VERSION 5.7 ;
  NOWIREEXTENSIONATPIN ON ;
  DIVIDERCHAR "/" ;
  BUSBITCHARS "[]" ;
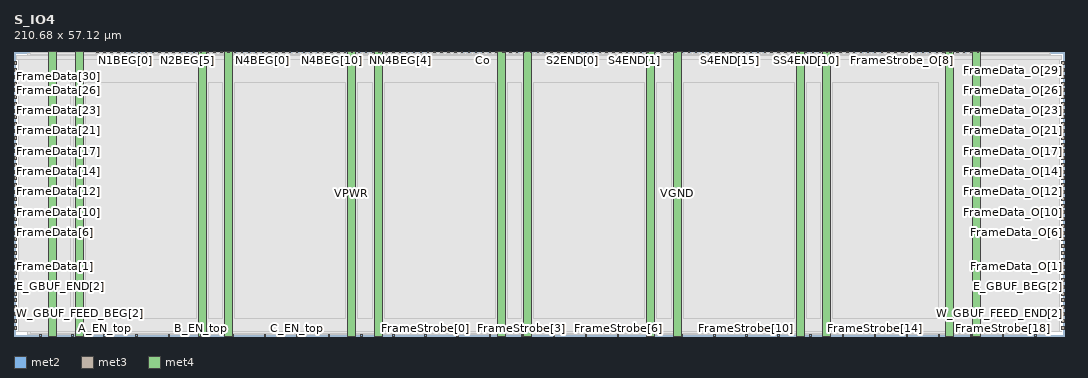
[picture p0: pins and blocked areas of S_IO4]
MACRO S_IO4
  CLASS BLOCK ;
  FOREIGN S_IO4 ;
  ORIGIN 0.000 0.000 ;
  SIZE 210.680 BY 57.120 ;
  PIN A_EN_top
    DIRECTION OUTPUT ;
    USE SIGNAL ;
    ANTENNADIFFAREA 0.702900 ;
    PORT
      LAYER met2 ;
        RECT 18.030 0.000 18.310 0.280 ;
    END
  END A_EN_top
  PIN A_IN_top
    DIRECTION OUTPUT ;
    USE SIGNAL ;
    ANTENNADIFFAREA 0.702900 ;
    PORT
      LAYER met2 ;
        RECT 11.590 0.000 11.870 0.280 ;
    END
  END A_IN_top
  PIN A_OUT_top
    DIRECTION INPUT ;
    USE SIGNAL ;
    ANTENNAGATEAREA 0.252000 ;
    PORT
      LAYER met2 ;
        RECT 5.150 0.000 5.430 0.280 ;
    END
  END A_OUT_top
  PIN B_EN_top
    DIRECTION OUTPUT ;
    USE SIGNAL ;
    ANTENNADIFFAREA 0.702900 ;
    PORT
      LAYER met2 ;
        RECT 37.350 0.000 37.630 0.280 ;
    END
  END B_EN_top
  PIN B_IN_top
    DIRECTION OUTPUT ;
    USE SIGNAL ;
    ANTENNADIFFAREA 0.702900 ;
    PORT
      LAYER met2 ;
        RECT 30.910 0.000 31.190 0.280 ;
    END
  END B_IN_top
  PIN B_OUT_top
    DIRECTION INPUT ;
    USE SIGNAL ;
    ANTENNAGATEAREA 0.252000 ;
    PORT
      LAYER met2 ;
        RECT 24.470 0.000 24.750 0.280 ;
    END
  END B_OUT_top
  PIN C_EN_top
    DIRECTION OUTPUT ;
    USE SIGNAL ;
    ANTENNADIFFAREA 0.702900 ;
    PORT
      LAYER met2 ;
        RECT 56.670 0.000 56.950 0.280 ;
    END
  END C_EN_top
  PIN C_IN_top
    DIRECTION OUTPUT ;
    USE SIGNAL ;
    ANTENNADIFFAREA 0.702900 ;
    PORT
      LAYER met2 ;
        RECT 50.230 0.000 50.510 0.280 ;
    END
  END C_IN_top
  PIN C_OUT_top
    DIRECTION INPUT ;
    USE SIGNAL ;
    ANTENNAGATEAREA 0.252000 ;
    PORT
      LAYER met2 ;
        RECT 43.790 0.000 44.070 0.280 ;
    END
  END C_OUT_top
  PIN Co
    DIRECTION OUTPUT ;
    USE SIGNAL ;
    PORT
      LAYER met2 ;
        RECT 93.930 56.840 94.210 57.120 ;
    END
  END Co
  PIN D_EN_top
    DIRECTION OUTPUT ;
    USE SIGNAL ;
    ANTENNADIFFAREA 0.702900 ;
    PORT
      LAYER met2 ;
        RECT 75.990 0.000 76.270 0.280 ;
    END
  END D_EN_top
  PIN D_IN_top
    DIRECTION OUTPUT ;
    USE SIGNAL ;
    ANTENNADIFFAREA 0.702900 ;
    PORT
      LAYER met2 ;
        RECT 69.550 0.000 69.830 0.280 ;
    END
  END D_IN_top
  PIN D_OUT_top
    DIRECTION INPUT ;
    USE SIGNAL ;
    ANTENNAGATEAREA 0.252000 ;
    PORT
      LAYER met2 ;
        RECT 63.110 0.000 63.390 0.280 ;
    END
  END D_OUT_top
  PIN E_GBUF_BEG[0]
    DIRECTION OUTPUT ;
    USE SIGNAL ;
    ANTENNADIFFAREA 0.702900 ;
    PORT
      LAYER met3 ;
        RECT 210.080 6.840 210.680 7.440 ;
    END
  END E_GBUF_BEG[0]
  PIN E_GBUF_BEG[1]
    DIRECTION OUTPUT ;
    USE SIGNAL ;
    ANTENNADIFFAREA 0.702900 ;
    PORT
      LAYER met3 ;
        RECT 210.080 8.200 210.680 8.800 ;
    END
  END E_GBUF_BEG[1]
  PIN E_GBUF_BEG[2]
    DIRECTION OUTPUT ;
    USE SIGNAL ;
    ANTENNADIFFAREA 0.702900 ;
    PORT
      LAYER met3 ;
        RECT 210.080 9.560 210.680 10.160 ;
    END
  END E_GBUF_BEG[2]
  PIN E_GBUF_BEG[3]
    DIRECTION OUTPUT ;
    USE SIGNAL ;
    ANTENNADIFFAREA 0.702900 ;
    PORT
      LAYER met3 ;
        RECT 210.080 10.920 210.680 11.520 ;
    END
  END E_GBUF_BEG[3]
  PIN E_GBUF_END[0]
    DIRECTION INPUT ;
    USE SIGNAL ;
    ANTENNAGATEAREA 0.954000 ;
    PORT
      LAYER met3 ;
        RECT 0.000 6.840 0.600 7.440 ;
    END
  END E_GBUF_END[0]
  PIN E_GBUF_END[1]
    DIRECTION INPUT ;
    USE SIGNAL ;
    ANTENNAGATEAREA 0.954000 ;
    PORT
      LAYER met3 ;
        RECT 0.000 8.200 0.600 8.800 ;
    END
  END E_GBUF_END[1]
  PIN E_GBUF_END[2]
    DIRECTION INPUT ;
    USE SIGNAL ;
    ANTENNAGATEAREA 0.954000 ;
    PORT
      LAYER met3 ;
        RECT 0.000 9.560 0.600 10.160 ;
    END
  END E_GBUF_END[2]
  PIN E_GBUF_END[3]
    DIRECTION INPUT ;
    USE SIGNAL ;
    ANTENNAGATEAREA 0.954000 ;
    PORT
      LAYER met3 ;
        RECT 0.000 10.920 0.600 11.520 ;
    END
  END E_GBUF_END[3]
  PIN FrameData[0]
    DIRECTION INPUT ;
    USE SIGNAL ;
    ANTENNAGATEAREA 0.795000 ;
    PORT
      LAYER met3 ;
        RECT 0.000 12.280 0.600 12.880 ;
    END
  END FrameData[0]
  PIN FrameData[10]
    DIRECTION INPUT ;
    USE SIGNAL ;
    ANTENNAGATEAREA 0.795000 ;
    PORT
      LAYER met3 ;
        RECT 0.000 25.880 0.600 26.480 ;
    END
  END FrameData[10]
  PIN FrameData[11]
    DIRECTION INPUT ;
    USE SIGNAL ;
    ANTENNAGATEAREA 0.795000 ;
    PORT
      LAYER met3 ;
        RECT 0.000 27.240 0.600 27.840 ;
    END
  END FrameData[11]
  PIN FrameData[12]
    DIRECTION INPUT ;
    USE SIGNAL ;
    ANTENNAGATEAREA 1.229700 ;
    ANTENNADIFFAREA 0.434700 ;
    PORT
      LAYER met3 ;
        RECT 0.000 28.600 0.600 29.200 ;
    END
  END FrameData[12]
  PIN FrameData[13]
    DIRECTION INPUT ;
    USE SIGNAL ;
    ANTENNAGATEAREA 0.795000 ;
    PORT
      LAYER met3 ;
        RECT 0.000 29.960 0.600 30.560 ;
    END
  END FrameData[13]
  PIN FrameData[14]
    DIRECTION INPUT ;
    USE SIGNAL ;
    ANTENNAGATEAREA 2.099100 ;
    ANTENNADIFFAREA 1.304100 ;
    PORT
      LAYER met3 ;
        RECT 0.000 31.320 0.600 31.920 ;
    END
  END FrameData[14]
  PIN FrameData[15]
    DIRECTION INPUT ;
    USE SIGNAL ;
    ANTENNAGATEAREA 1.229700 ;
    ANTENNADIFFAREA 0.434700 ;
    PORT
      LAYER met3 ;
        RECT 0.000 32.680 0.600 33.280 ;
    END
  END FrameData[15]
  PIN FrameData[16]
    DIRECTION INPUT ;
    USE SIGNAL ;
    ANTENNAGATEAREA 0.795000 ;
    PORT
      LAYER met3 ;
        RECT 0.000 34.040 0.600 34.640 ;
    END
  END FrameData[16]
  PIN FrameData[17]
    DIRECTION INPUT ;
    USE SIGNAL ;
    ANTENNAGATEAREA 1.664400 ;
    ANTENNADIFFAREA 0.869400 ;
    PORT
      LAYER met3 ;
        RECT 0.000 35.400 0.600 36.000 ;
    END
  END FrameData[17]
  PIN FrameData[18]
    DIRECTION INPUT ;
    USE SIGNAL ;
    ANTENNAGATEAREA 1.664400 ;
    ANTENNADIFFAREA 0.869400 ;
    PORT
      LAYER met3 ;
        RECT 0.000 36.760 0.600 37.360 ;
    END
  END FrameData[18]
  PIN FrameData[19]
    DIRECTION INPUT ;
    USE SIGNAL ;
    ANTENNAGATEAREA 1.664400 ;
    ANTENNADIFFAREA 0.869400 ;
    PORT
      LAYER met3 ;
        RECT 0.000 38.120 0.600 38.720 ;
    END
  END FrameData[19]
  PIN FrameData[1]
    DIRECTION INPUT ;
    USE SIGNAL ;
    ANTENNAGATEAREA 0.795000 ;
    PORT
      LAYER met3 ;
        RECT 0.000 13.640 0.600 14.240 ;
    END
  END FrameData[1]
  PIN FrameData[20]
    DIRECTION INPUT ;
    USE SIGNAL ;
    ANTENNAGATEAREA 0.954000 ;
    PORT
      LAYER met3 ;
        RECT 0.000 39.480 0.600 40.080 ;
    END
  END FrameData[20]
  PIN FrameData[21]
    DIRECTION INPUT ;
    USE SIGNAL ;
    ANTENNAGATEAREA 0.954000 ;
    PORT
      LAYER met3 ;
        RECT 0.000 40.840 0.600 41.440 ;
    END
  END FrameData[21]
  PIN FrameData[22]
    DIRECTION INPUT ;
    USE SIGNAL ;
    ANTENNAGATEAREA 1.823400 ;
    ANTENNADIFFAREA 0.869400 ;
    PORT
      LAYER met3 ;
        RECT 0.000 42.200 0.600 42.800 ;
    END
  END FrameData[22]
  PIN FrameData[23]
    DIRECTION INPUT ;
    USE SIGNAL ;
    ANTENNAGATEAREA 0.954000 ;
    PORT
      LAYER met3 ;
        RECT 0.000 43.560 0.600 44.160 ;
    END
  END FrameData[23]
  PIN FrameData[24]
    DIRECTION INPUT ;
    USE SIGNAL ;
    ANTENNAGATEAREA 0.954000 ;
    PORT
      LAYER met3 ;
        RECT 0.000 44.920 0.600 45.520 ;
    END
  END FrameData[24]
  PIN FrameData[25]
    DIRECTION INPUT ;
    USE SIGNAL ;
    ANTENNAGATEAREA 0.954000 ;
    PORT
      LAYER met3 ;
        RECT 0.000 46.280 0.600 46.880 ;
    END
  END FrameData[25]
  PIN FrameData[26]
    DIRECTION INPUT ;
    USE SIGNAL ;
    ANTENNAGATEAREA 2.692800 ;
    ANTENNADIFFAREA 1.738800 ;
    PORT
      LAYER met3 ;
        RECT 0.000 47.640 0.600 48.240 ;
    END
  END FrameData[26]
  PIN FrameData[27]
    DIRECTION INPUT ;
    USE SIGNAL ;
    ANTENNAGATEAREA 2.692800 ;
    ANTENNADIFFAREA 1.738800 ;
    PORT
      LAYER met3 ;
        RECT 0.000 49.000 0.600 49.600 ;
    END
  END FrameData[27]
  PIN FrameData[28]
    DIRECTION INPUT ;
    USE SIGNAL ;
    ANTENNAGATEAREA 0.954000 ;
    PORT
      LAYER met3 ;
        RECT 0.000 50.360 0.600 50.960 ;
    END
  END FrameData[28]
  PIN FrameData[29]
    DIRECTION INPUT ;
    USE SIGNAL ;
    ANTENNAGATEAREA 1.388700 ;
    ANTENNADIFFAREA 0.434700 ;
    PORT
      LAYER met3 ;
        RECT 0.000 51.720 0.600 52.320 ;
    END
  END FrameData[29]
  PIN FrameData[2]
    DIRECTION INPUT ;
    USE SIGNAL ;
    ANTENNAGATEAREA 0.795000 ;
    PORT
      LAYER met3 ;
        RECT 0.000 15.000 0.600 15.600 ;
    END
  END FrameData[2]
  PIN FrameData[30]
    DIRECTION INPUT ;
    USE SIGNAL ;
    ANTENNAGATEAREA 1.823400 ;
    ANTENNADIFFAREA 0.869400 ;
    PORT
      LAYER met3 ;
        RECT 0.000 53.080 0.600 53.680 ;
    END
  END FrameData[30]
  PIN FrameData[31]
    DIRECTION INPUT ;
    USE SIGNAL ;
    ANTENNAGATEAREA 2.692800 ;
    ANTENNADIFFAREA 1.738800 ;
    PORT
      LAYER met3 ;
        RECT 0.000 54.440 0.600 55.040 ;
    END
  END FrameData[31]
  PIN FrameData[3]
    DIRECTION INPUT ;
    USE SIGNAL ;
    ANTENNAGATEAREA 0.795000 ;
    PORT
      LAYER met3 ;
        RECT 0.000 16.360 0.600 16.960 ;
    END
  END FrameData[3]
  PIN FrameData[4]
    DIRECTION INPUT ;
    USE SIGNAL ;
    ANTENNAGATEAREA 0.795000 ;
    PORT
      LAYER met3 ;
        RECT 0.000 17.720 0.600 18.320 ;
    END
  END FrameData[4]
  PIN FrameData[5]
    DIRECTION INPUT ;
    USE SIGNAL ;
    ANTENNAGATEAREA 2.968500 ;
    ANTENNADIFFAREA 2.173500 ;
    PORT
      LAYER met3 ;
        RECT 0.000 19.080 0.600 19.680 ;
    END
  END FrameData[5]
  PIN FrameData[6]
    DIRECTION INPUT ;
    USE SIGNAL ;
    ANTENNAGATEAREA 2.533800 ;
    ANTENNADIFFAREA 1.738800 ;
    PORT
      LAYER met3 ;
        RECT 0.000 20.440 0.600 21.040 ;
    END
  END FrameData[6]
  PIN FrameData[7]
    DIRECTION INPUT ;
    USE SIGNAL ;
    ANTENNAGATEAREA 2.099100 ;
    ANTENNADIFFAREA 1.304100 ;
    PORT
      LAYER met3 ;
        RECT 0.000 21.800 0.600 22.400 ;
    END
  END FrameData[7]
  PIN FrameData[8]
    DIRECTION INPUT ;
    USE SIGNAL ;
    ANTENNAGATEAREA 0.795000 ;
    PORT
      LAYER met3 ;
        RECT 0.000 23.160 0.600 23.760 ;
    END
  END FrameData[8]
  PIN FrameData[9]
    DIRECTION INPUT ;
    USE SIGNAL ;
    ANTENNAGATEAREA 0.795000 ;
    PORT
      LAYER met3 ;
        RECT 0.000 24.520 0.600 25.120 ;
    END
  END FrameData[9]
  PIN FrameData_O[0]
    DIRECTION OUTPUT ;
    USE SIGNAL ;
    ANTENNADIFFAREA 0.702900 ;
    PORT
      LAYER met3 ;
        RECT 210.080 12.280 210.680 12.880 ;
    END
  END FrameData_O[0]
  PIN FrameData_O[10]
    DIRECTION OUTPUT ;
    USE SIGNAL ;
    ANTENNADIFFAREA 0.702900 ;
    PORT
      LAYER met3 ;
        RECT 210.080 25.880 210.680 26.480 ;
    END
  END FrameData_O[10]
  PIN FrameData_O[11]
    DIRECTION OUTPUT ;
    USE SIGNAL ;
    ANTENNADIFFAREA 0.702900 ;
    PORT
      LAYER met3 ;
        RECT 210.080 27.240 210.680 27.840 ;
    END
  END FrameData_O[11]
  PIN FrameData_O[12]
    DIRECTION OUTPUT ;
    USE SIGNAL ;
    ANTENNADIFFAREA 0.702900 ;
    PORT
      LAYER met3 ;
        RECT 210.080 28.600 210.680 29.200 ;
    END
  END FrameData_O[12]
  PIN FrameData_O[13]
    DIRECTION OUTPUT ;
    USE SIGNAL ;
    ANTENNADIFFAREA 0.702900 ;
    PORT
      LAYER met3 ;
        RECT 210.080 29.960 210.680 30.560 ;
    END
  END FrameData_O[13]
  PIN FrameData_O[14]
    DIRECTION OUTPUT ;
    USE SIGNAL ;
    ANTENNADIFFAREA 0.702900 ;
    PORT
      LAYER met3 ;
        RECT 210.080 31.320 210.680 31.920 ;
    END
  END FrameData_O[14]
  PIN FrameData_O[15]
    DIRECTION OUTPUT ;
    USE SIGNAL ;
    ANTENNADIFFAREA 0.702900 ;
    PORT
      LAYER met3 ;
        RECT 210.080 32.680 210.680 33.280 ;
    END
  END FrameData_O[15]
  PIN FrameData_O[16]
    DIRECTION OUTPUT ;
    USE SIGNAL ;
    ANTENNADIFFAREA 0.702900 ;
    PORT
      LAYER met3 ;
        RECT 210.080 34.040 210.680 34.640 ;
    END
  END FrameData_O[16]
  PIN FrameData_O[17]
    DIRECTION OUTPUT ;
    USE SIGNAL ;
    ANTENNADIFFAREA 0.702900 ;
    PORT
      LAYER met3 ;
        RECT 210.080 35.400 210.680 36.000 ;
    END
  END FrameData_O[17]
  PIN FrameData_O[18]
    DIRECTION OUTPUT ;
    USE SIGNAL ;
    ANTENNADIFFAREA 0.702900 ;
    PORT
      LAYER met3 ;
        RECT 210.080 36.760 210.680 37.360 ;
    END
  END FrameData_O[18]
  PIN FrameData_O[19]
    DIRECTION OUTPUT ;
    USE SIGNAL ;
    ANTENNADIFFAREA 0.702900 ;
    PORT
      LAYER met3 ;
        RECT 210.080 38.120 210.680 38.720 ;
    END
  END FrameData_O[19]
  PIN FrameData_O[1]
    DIRECTION OUTPUT ;
    USE SIGNAL ;
    ANTENNADIFFAREA 0.702900 ;
    PORT
      LAYER met3 ;
        RECT 210.080 13.640 210.680 14.240 ;
    END
  END FrameData_O[1]
  PIN FrameData_O[20]
    DIRECTION OUTPUT ;
    USE SIGNAL ;
    ANTENNADIFFAREA 0.702900 ;
    PORT
      LAYER met3 ;
        RECT 210.080 39.480 210.680 40.080 ;
    END
  END FrameData_O[20]
  PIN FrameData_O[21]
    DIRECTION OUTPUT ;
    USE SIGNAL ;
    ANTENNADIFFAREA 0.702900 ;
    PORT
      LAYER met3 ;
        RECT 210.080 40.840 210.680 41.440 ;
    END
  END FrameData_O[21]
  PIN FrameData_O[22]
    DIRECTION OUTPUT ;
    USE SIGNAL ;
    ANTENNADIFFAREA 0.702900 ;
    PORT
      LAYER met3 ;
        RECT 210.080 42.200 210.680 42.800 ;
    END
  END FrameData_O[22]
  PIN FrameData_O[23]
    DIRECTION OUTPUT ;
    USE SIGNAL ;
    ANTENNADIFFAREA 0.702900 ;
    PORT
      LAYER met3 ;
        RECT 210.080 43.560 210.680 44.160 ;
    END
  END FrameData_O[23]
  PIN FrameData_O[24]
    DIRECTION OUTPUT ;
    USE SIGNAL ;
    ANTENNADIFFAREA 0.702900 ;
    PORT
      LAYER met3 ;
        RECT 210.080 44.920 210.680 45.520 ;
    END
  END FrameData_O[24]
  PIN FrameData_O[25]
    DIRECTION OUTPUT ;
    USE SIGNAL ;
    ANTENNADIFFAREA 0.702900 ;
    PORT
      LAYER met3 ;
        RECT 210.080 46.280 210.680 46.880 ;
    END
  END FrameData_O[25]
  PIN FrameData_O[26]
    DIRECTION OUTPUT ;
    USE SIGNAL ;
    ANTENNADIFFAREA 0.702900 ;
    PORT
      LAYER met3 ;
        RECT 210.080 47.640 210.680 48.240 ;
    END
  END FrameData_O[26]
  PIN FrameData_O[27]
    DIRECTION OUTPUT ;
    USE SIGNAL ;
    ANTENNADIFFAREA 0.702900 ;
    PORT
      LAYER met3 ;
        RECT 210.080 49.000 210.680 49.600 ;
    END
  END FrameData_O[27]
  PIN FrameData_O[28]
    DIRECTION OUTPUT ;
    USE SIGNAL ;
    ANTENNADIFFAREA 0.702900 ;
    PORT
      LAYER met3 ;
        RECT 210.080 50.360 210.680 50.960 ;
    END
  END FrameData_O[28]
  PIN FrameData_O[29]
    DIRECTION OUTPUT ;
    USE SIGNAL ;
    ANTENNADIFFAREA 0.702900 ;
    PORT
      LAYER met3 ;
        RECT 210.080 51.720 210.680 52.320 ;
    END
  END FrameData_O[29]
  PIN FrameData_O[2]
    DIRECTION OUTPUT ;
    USE SIGNAL ;
    ANTENNADIFFAREA 0.702900 ;
    PORT
      LAYER met3 ;
        RECT 210.080 15.000 210.680 15.600 ;
    END
  END FrameData_O[2]
  PIN FrameData_O[30]
    DIRECTION OUTPUT ;
    USE SIGNAL ;
    ANTENNADIFFAREA 0.702900 ;
    PORT
      LAYER met3 ;
        RECT 210.080 53.080 210.680 53.680 ;
    END
  END FrameData_O[30]
  PIN FrameData_O[31]
    DIRECTION OUTPUT ;
    USE SIGNAL ;
    ANTENNADIFFAREA 0.702900 ;
    PORT
      LAYER met3 ;
        RECT 210.080 54.440 210.680 55.040 ;
    END
  END FrameData_O[31]
  PIN FrameData_O[3]
    DIRECTION OUTPUT ;
    USE SIGNAL ;
    ANTENNADIFFAREA 0.702900 ;
    PORT
      LAYER met3 ;
        RECT 210.080 16.360 210.680 16.960 ;
    END
  END FrameData_O[3]
  PIN FrameData_O[4]
    DIRECTION OUTPUT ;
    USE SIGNAL ;
    ANTENNADIFFAREA 0.702900 ;
    PORT
      LAYER met3 ;
        RECT 210.080 17.720 210.680 18.320 ;
    END
  END FrameData_O[4]
  PIN FrameData_O[5]
    DIRECTION OUTPUT ;
    USE SIGNAL ;
    ANTENNADIFFAREA 0.702900 ;
    PORT
      LAYER met3 ;
        RECT 210.080 19.080 210.680 19.680 ;
    END
  END FrameData_O[5]
  PIN FrameData_O[6]
    DIRECTION OUTPUT ;
    USE SIGNAL ;
    ANTENNADIFFAREA 0.702900 ;
    PORT
      LAYER met3 ;
        RECT 210.080 20.440 210.680 21.040 ;
    END
  END FrameData_O[6]
  PIN FrameData_O[7]
    DIRECTION OUTPUT ;
    USE SIGNAL ;
    ANTENNADIFFAREA 0.702900 ;
    PORT
      LAYER met3 ;
        RECT 210.080 21.800 210.680 22.400 ;
    END
  END FrameData_O[7]
  PIN FrameData_O[8]
    DIRECTION OUTPUT ;
    USE SIGNAL ;
    ANTENNADIFFAREA 0.702900 ;
    PORT
      LAYER met3 ;
        RECT 210.080 23.160 210.680 23.760 ;
    END
  END FrameData_O[8]
  PIN FrameData_O[9]
    DIRECTION OUTPUT ;
    USE SIGNAL ;
    ANTENNADIFFAREA 0.702900 ;
    PORT
      LAYER met3 ;
        RECT 210.080 24.520 210.680 25.120 ;
    END
  END FrameData_O[9]
  PIN FrameStrobe[0]
    DIRECTION INPUT ;
    USE SIGNAL ;
    ANTENNAGATEAREA 5.247000 ;
    PORT
      LAYER met2 ;
        RECT 82.430 0.000 82.710 0.280 ;
    END
  END FrameStrobe[0]
  PIN FrameStrobe[10]
    DIRECTION INPUT ;
    USE SIGNAL ;
    ANTENNAGATEAREA 0.159000 ;
    PORT
      LAYER met2 ;
        RECT 146.830 0.000 147.110 0.280 ;
    END
  END FrameStrobe[10]
  PIN FrameStrobe[11]
    DIRECTION INPUT ;
    USE SIGNAL ;
    ANTENNAGATEAREA 0.159000 ;
    PORT
      LAYER met2 ;
        RECT 153.270 0.000 153.550 0.280 ;
    END
  END FrameStrobe[11]
  PIN FrameStrobe[12]
    DIRECTION INPUT ;
    USE SIGNAL ;
    ANTENNAGATEAREA 0.159000 ;
    PORT
      LAYER met2 ;
        RECT 159.710 0.000 159.990 0.280 ;
    END
  END FrameStrobe[12]
  PIN FrameStrobe[13]
    DIRECTION INPUT ;
    USE SIGNAL ;
    ANTENNAGATEAREA 0.159000 ;
    PORT
      LAYER met2 ;
        RECT 166.150 0.000 166.430 0.280 ;
    END
  END FrameStrobe[13]
  PIN FrameStrobe[14]
    DIRECTION INPUT ;
    USE SIGNAL ;
    ANTENNAGATEAREA 0.159000 ;
    PORT
      LAYER met2 ;
        RECT 172.590 0.000 172.870 0.280 ;
    END
  END FrameStrobe[14]
  PIN FrameStrobe[15]
    DIRECTION INPUT ;
    USE SIGNAL ;
    ANTENNAGATEAREA 0.159000 ;
    PORT
      LAYER met2 ;
        RECT 179.030 0.000 179.310 0.280 ;
    END
  END FrameStrobe[15]
  PIN FrameStrobe[16]
    DIRECTION INPUT ;
    USE SIGNAL ;
    ANTENNAGATEAREA 0.159000 ;
    PORT
      LAYER met2 ;
        RECT 185.470 0.000 185.750 0.280 ;
    END
  END FrameStrobe[16]
  PIN FrameStrobe[17]
    DIRECTION INPUT ;
    USE SIGNAL ;
    ANTENNAGATEAREA 0.159000 ;
    PORT
      LAYER met2 ;
        RECT 191.910 0.000 192.190 0.280 ;
    END
  END FrameStrobe[17]
  PIN FrameStrobe[18]
    DIRECTION INPUT ;
    USE SIGNAL ;
    ANTENNAGATEAREA 0.159000 ;
    PORT
      LAYER met2 ;
        RECT 198.350 0.000 198.630 0.280 ;
    END
  END FrameStrobe[18]
  PIN FrameStrobe[19]
    DIRECTION INPUT ;
    USE SIGNAL ;
    ANTENNAGATEAREA 0.159000 ;
    PORT
      LAYER met2 ;
        RECT 204.790 0.000 205.070 0.280 ;
    END
  END FrameStrobe[19]
  PIN FrameStrobe[1]
    DIRECTION INPUT ;
    USE SIGNAL ;
    ANTENNAGATEAREA 5.247000 ;
    PORT
      LAYER met2 ;
        RECT 88.870 0.000 89.150 0.280 ;
    END
  END FrameStrobe[1]
  PIN FrameStrobe[2]
    DIRECTION INPUT ;
    USE SIGNAL ;
    ANTENNAGATEAREA 5.247000 ;
    PORT
      LAYER met2 ;
        RECT 95.310 0.000 95.590 0.280 ;
    END
  END FrameStrobe[2]
  PIN FrameStrobe[3]
    DIRECTION INPUT ;
    USE SIGNAL ;
    ANTENNAGATEAREA 5.247000 ;
    PORT
      LAYER met2 ;
        RECT 101.750 0.000 102.030 0.280 ;
    END
  END FrameStrobe[3]
  PIN FrameStrobe[4]
    DIRECTION INPUT ;
    USE SIGNAL ;
    ANTENNAGATEAREA 2.067000 ;
    PORT
      LAYER met2 ;
        RECT 108.190 0.000 108.470 0.280 ;
    END
  END FrameStrobe[4]
  PIN FrameStrobe[5]
    DIRECTION INPUT ;
    USE SIGNAL ;
    ANTENNAGATEAREA 0.159000 ;
    PORT
      LAYER met2 ;
        RECT 114.630 0.000 114.910 0.280 ;
    END
  END FrameStrobe[5]
  PIN FrameStrobe[6]
    DIRECTION INPUT ;
    USE SIGNAL ;
    ANTENNAGATEAREA 0.159000 ;
    PORT
      LAYER met2 ;
        RECT 121.070 0.000 121.350 0.280 ;
    END
  END FrameStrobe[6]
  PIN FrameStrobe[7]
    DIRECTION INPUT ;
    USE SIGNAL ;
    ANTENNAGATEAREA 0.593700 ;
    ANTENNADIFFAREA 0.434700 ;
    PORT
      LAYER met2 ;
        RECT 127.510 0.000 127.790 0.280 ;
    END
  END FrameStrobe[7]
  PIN FrameStrobe[8]
    DIRECTION INPUT ;
    USE SIGNAL ;
    ANTENNAGATEAREA 0.159000 ;
    PORT
      LAYER met2 ;
        RECT 133.950 0.000 134.230 0.280 ;
    END
  END FrameStrobe[8]
  PIN FrameStrobe[9]
    DIRECTION INPUT ;
    USE SIGNAL ;
    ANTENNAGATEAREA 0.159000 ;
    PORT
      LAYER met2 ;
        RECT 140.390 0.000 140.670 0.280 ;
    END
  END FrameStrobe[9]
  PIN FrameStrobe_O[0]
    DIRECTION OUTPUT ;
    USE SIGNAL ;
    ANTENNADIFFAREA 0.702900 ;
    PORT
      LAYER met2 ;
        RECT 167.070 56.840 167.350 57.120 ;
    END
  END FrameStrobe_O[0]
  PIN FrameStrobe_O[10]
    DIRECTION OUTPUT ;
    USE SIGNAL ;
    ANTENNADIFFAREA 0.702900 ;
    PORT
      LAYER met2 ;
        RECT 180.870 56.840 181.150 57.120 ;
    END
  END FrameStrobe_O[10]
  PIN FrameStrobe_O[11]
    DIRECTION OUTPUT ;
    USE SIGNAL ;
    ANTENNADIFFAREA 0.702900 ;
    PORT
      LAYER met2 ;
        RECT 182.250 56.840 182.530 57.120 ;
    END
  END FrameStrobe_O[11]
  PIN FrameStrobe_O[12]
    DIRECTION OUTPUT ;
    USE SIGNAL ;
    ANTENNADIFFAREA 0.702900 ;
    PORT
      LAYER met2 ;
        RECT 183.630 56.840 183.910 57.120 ;
    END
  END FrameStrobe_O[12]
  PIN FrameStrobe_O[13]
    DIRECTION OUTPUT ;
    USE SIGNAL ;
    ANTENNADIFFAREA 0.702900 ;
    PORT
      LAYER met2 ;
        RECT 185.010 56.840 185.290 57.120 ;
    END
  END FrameStrobe_O[13]
  PIN FrameStrobe_O[14]
    DIRECTION OUTPUT ;
    USE SIGNAL ;
    ANTENNADIFFAREA 0.702900 ;
    PORT
      LAYER met2 ;
        RECT 186.390 56.840 186.670 57.120 ;
    END
  END FrameStrobe_O[14]
  PIN FrameStrobe_O[15]
    DIRECTION OUTPUT ;
    USE SIGNAL ;
    ANTENNADIFFAREA 0.702900 ;
    PORT
      LAYER met2 ;
        RECT 187.770 56.840 188.050 57.120 ;
    END
  END FrameStrobe_O[15]
  PIN FrameStrobe_O[16]
    DIRECTION OUTPUT ;
    USE SIGNAL ;
    ANTENNADIFFAREA 0.702900 ;
    PORT
      LAYER met2 ;
        RECT 189.150 56.840 189.430 57.120 ;
    END
  END FrameStrobe_O[16]
  PIN FrameStrobe_O[17]
    DIRECTION OUTPUT ;
    USE SIGNAL ;
    ANTENNADIFFAREA 0.702900 ;
    PORT
      LAYER met2 ;
        RECT 190.530 56.840 190.810 57.120 ;
    END
  END FrameStrobe_O[17]
  PIN FrameStrobe_O[18]
    DIRECTION OUTPUT ;
    USE SIGNAL ;
    ANTENNADIFFAREA 0.702900 ;
    PORT
      LAYER met2 ;
        RECT 191.910 56.840 192.190 57.120 ;
    END
  END FrameStrobe_O[18]
  PIN FrameStrobe_O[19]
    DIRECTION OUTPUT ;
    USE SIGNAL ;
    ANTENNADIFFAREA 0.702900 ;
    PORT
      LAYER met2 ;
        RECT 193.290 56.840 193.570 57.120 ;
    END
  END FrameStrobe_O[19]
  PIN FrameStrobe_O[1]
    DIRECTION OUTPUT ;
    USE SIGNAL ;
    ANTENNADIFFAREA 0.702900 ;
    PORT
      LAYER met2 ;
        RECT 168.450 56.840 168.730 57.120 ;
    END
  END FrameStrobe_O[1]
  PIN FrameStrobe_O[2]
    DIRECTION OUTPUT ;
    USE SIGNAL ;
    ANTENNADIFFAREA 0.702900 ;
    PORT
      LAYER met2 ;
        RECT 169.830 56.840 170.110 57.120 ;
    END
  END FrameStrobe_O[2]
  PIN FrameStrobe_O[3]
    DIRECTION OUTPUT ;
    USE SIGNAL ;
    ANTENNADIFFAREA 0.702900 ;
    PORT
      LAYER met2 ;
        RECT 171.210 56.840 171.490 57.120 ;
    END
  END FrameStrobe_O[3]
  PIN FrameStrobe_O[4]
    DIRECTION OUTPUT ;
    USE SIGNAL ;
    ANTENNADIFFAREA 0.702900 ;
    PORT
      LAYER met2 ;
        RECT 172.590 56.840 172.870 57.120 ;
    END
  END FrameStrobe_O[4]
  PIN FrameStrobe_O[5]
    DIRECTION OUTPUT ;
    USE SIGNAL ;
    ANTENNADIFFAREA 0.702900 ;
    PORT
      LAYER met2 ;
        RECT 173.970 56.840 174.250 57.120 ;
    END
  END FrameStrobe_O[5]
  PIN FrameStrobe_O[6]
    DIRECTION OUTPUT ;
    USE SIGNAL ;
    ANTENNADIFFAREA 0.702900 ;
    PORT
      LAYER met2 ;
        RECT 175.350 56.840 175.630 57.120 ;
    END
  END FrameStrobe_O[6]
  PIN FrameStrobe_O[7]
    DIRECTION OUTPUT ;
    USE SIGNAL ;
    ANTENNADIFFAREA 0.702900 ;
    PORT
      LAYER met2 ;
        RECT 176.730 56.840 177.010 57.120 ;
    END
  END FrameStrobe_O[7]
  PIN FrameStrobe_O[8]
    DIRECTION OUTPUT ;
    USE SIGNAL ;
    ANTENNADIFFAREA 0.702900 ;
    PORT
      LAYER met2 ;
        RECT 178.110 56.840 178.390 57.120 ;
    END
  END FrameStrobe_O[8]
  PIN FrameStrobe_O[9]
    DIRECTION OUTPUT ;
    USE SIGNAL ;
    ANTENNADIFFAREA 0.702900 ;
    PORT
      LAYER met2 ;
        RECT 179.490 56.840 179.770 57.120 ;
    END
  END FrameStrobe_O[9]
  PIN N1BEG[0]
    DIRECTION OUTPUT ;
    USE SIGNAL ;
    ANTENNADIFFAREA 0.702900 ;
    PORT
      LAYER met2 ;
        RECT 22.170 56.840 22.450 57.120 ;
    END
  END N1BEG[0]
  PIN N1BEG[1]
    DIRECTION OUTPUT ;
    USE SIGNAL ;
    ANTENNADIFFAREA 0.702900 ;
    PORT
      LAYER met2 ;
        RECT 23.550 56.840 23.830 57.120 ;
    END
  END N1BEG[1]
  PIN N1BEG[2]
    DIRECTION OUTPUT ;
    USE SIGNAL ;
    ANTENNADIFFAREA 0.702900 ;
    PORT
      LAYER met2 ;
        RECT 24.930 56.840 25.210 57.120 ;
    END
  END N1BEG[2]
  PIN N1BEG[3]
    DIRECTION OUTPUT ;
    USE SIGNAL ;
    ANTENNADIFFAREA 0.702900 ;
    PORT
      LAYER met2 ;
        RECT 26.310 56.840 26.590 57.120 ;
    END
  END N1BEG[3]
  PIN N2BEG[0]
    DIRECTION OUTPUT ;
    USE SIGNAL ;
    ANTENNADIFFAREA 0.702900 ;
    PORT
      LAYER met2 ;
        RECT 27.690 56.840 27.970 57.120 ;
    END
  END N2BEG[0]
  PIN N2BEG[1]
    DIRECTION OUTPUT ;
    USE SIGNAL ;
    ANTENNADIFFAREA 0.702900 ;
    PORT
      LAYER met2 ;
        RECT 29.070 56.840 29.350 57.120 ;
    END
  END N2BEG[1]
  PIN N2BEG[2]
    DIRECTION OUTPUT ;
    USE SIGNAL ;
    ANTENNADIFFAREA 0.702900 ;
    PORT
      LAYER met2 ;
        RECT 30.450 56.840 30.730 57.120 ;
    END
  END N2BEG[2]
  PIN N2BEG[3]
    DIRECTION OUTPUT ;
    USE SIGNAL ;
    ANTENNADIFFAREA 0.702900 ;
    PORT
      LAYER met2 ;
        RECT 31.830 56.840 32.110 57.120 ;
    END
  END N2BEG[3]
  PIN N2BEG[4]
    DIRECTION OUTPUT ;
    USE SIGNAL ;
    ANTENNADIFFAREA 0.702900 ;
    PORT
      LAYER met2 ;
        RECT 33.210 56.840 33.490 57.120 ;
    END
  END N2BEG[4]
  PIN N2BEG[5]
    DIRECTION OUTPUT ;
    USE SIGNAL ;
    ANTENNADIFFAREA 0.702900 ;
    PORT
      LAYER met2 ;
        RECT 34.590 56.840 34.870 57.120 ;
    END
  END N2BEG[5]
  PIN N2BEG[6]
    DIRECTION OUTPUT ;
    USE SIGNAL ;
    ANTENNADIFFAREA 0.702900 ;
    PORT
      LAYER met2 ;
        RECT 35.970 56.840 36.250 57.120 ;
    END
  END N2BEG[6]
  PIN N2BEG[7]
    DIRECTION OUTPUT ;
    USE SIGNAL ;
    ANTENNADIFFAREA 0.702900 ;
    PORT
      LAYER met2 ;
        RECT 37.350 56.840 37.630 57.120 ;
    END
  END N2BEG[7]
  PIN N2BEGb[0]
    DIRECTION OUTPUT ;
    USE SIGNAL ;
    ANTENNADIFFAREA 0.702900 ;
    PORT
      LAYER met2 ;
        RECT 38.730 56.840 39.010 57.120 ;
    END
  END N2BEGb[0]
  PIN N2BEGb[1]
    DIRECTION OUTPUT ;
    USE SIGNAL ;
    ANTENNADIFFAREA 0.702900 ;
    PORT
      LAYER met2 ;
        RECT 40.110 56.840 40.390 57.120 ;
    END
  END N2BEGb[1]
  PIN N2BEGb[2]
    DIRECTION OUTPUT ;
    USE SIGNAL ;
    ANTENNADIFFAREA 0.702900 ;
    PORT
      LAYER met2 ;
        RECT 41.490 56.840 41.770 57.120 ;
    END
  END N2BEGb[2]
  PIN N2BEGb[3]
    DIRECTION OUTPUT ;
    USE SIGNAL ;
    ANTENNADIFFAREA 0.702900 ;
    PORT
      LAYER met2 ;
        RECT 42.870 56.840 43.150 57.120 ;
    END
  END N2BEGb[3]
  PIN N2BEGb[4]
    DIRECTION OUTPUT ;
    USE SIGNAL ;
    ANTENNADIFFAREA 0.702900 ;
    PORT
      LAYER met2 ;
        RECT 44.250 56.840 44.530 57.120 ;
    END
  END N2BEGb[4]
  PIN N2BEGb[5]
    DIRECTION OUTPUT ;
    USE SIGNAL ;
    ANTENNADIFFAREA 0.702900 ;
    PORT
      LAYER met2 ;
        RECT 45.630 56.840 45.910 57.120 ;
    END
  END N2BEGb[5]
  PIN N2BEGb[6]
    DIRECTION OUTPUT ;
    USE SIGNAL ;
    ANTENNADIFFAREA 0.702900 ;
    PORT
      LAYER met2 ;
        RECT 47.010 56.840 47.290 57.120 ;
    END
  END N2BEGb[6]
  PIN N2BEGb[7]
    DIRECTION OUTPUT ;
    USE SIGNAL ;
    ANTENNADIFFAREA 0.702900 ;
    PORT
      LAYER met2 ;
        RECT 48.390 56.840 48.670 57.120 ;
    END
  END N2BEGb[7]
  PIN N4BEG[0]
    DIRECTION OUTPUT ;
    USE SIGNAL ;
    ANTENNADIFFAREA 0.702900 ;
    PORT
      LAYER met2 ;
        RECT 49.770 56.840 50.050 57.120 ;
    END
  END N4BEG[0]
  PIN N4BEG[10]
    DIRECTION OUTPUT ;
    USE SIGNAL ;
    ANTENNADIFFAREA 0.702900 ;
    PORT
      LAYER met2 ;
        RECT 63.570 56.840 63.850 57.120 ;
    END
  END N4BEG[10]
  PIN N4BEG[11]
    DIRECTION OUTPUT ;
    USE SIGNAL ;
    ANTENNADIFFAREA 0.702900 ;
    PORT
      LAYER met2 ;
        RECT 64.950 56.840 65.230 57.120 ;
    END
  END N4BEG[11]
  PIN N4BEG[12]
    DIRECTION OUTPUT ;
    USE SIGNAL ;
    ANTENNADIFFAREA 0.702900 ;
    PORT
      LAYER met2 ;
        RECT 66.330 56.840 66.610 57.120 ;
    END
  END N4BEG[12]
  PIN N4BEG[13]
    DIRECTION OUTPUT ;
    USE SIGNAL ;
    ANTENNADIFFAREA 0.702900 ;
    PORT
      LAYER met2 ;
        RECT 67.710 56.840 67.990 57.120 ;
    END
  END N4BEG[13]
  PIN N4BEG[14]
    DIRECTION OUTPUT ;
    USE SIGNAL ;
    ANTENNADIFFAREA 0.702900 ;
    PORT
      LAYER met2 ;
        RECT 69.090 56.840 69.370 57.120 ;
    END
  END N4BEG[14]
  PIN N4BEG[15]
    DIRECTION OUTPUT ;
    USE SIGNAL ;
    ANTENNADIFFAREA 0.702900 ;
    PORT
      LAYER met2 ;
        RECT 70.470 56.840 70.750 57.120 ;
    END
  END N4BEG[15]
  PIN N4BEG[1]
    DIRECTION OUTPUT ;
    USE SIGNAL ;
    ANTENNADIFFAREA 0.702900 ;
    PORT
      LAYER met2 ;
        RECT 51.150 56.840 51.430 57.120 ;
    END
  END N4BEG[1]
  PIN N4BEG[2]
    DIRECTION OUTPUT ;
    USE SIGNAL ;
    ANTENNADIFFAREA 0.702900 ;
    PORT
      LAYER met2 ;
        RECT 52.530 56.840 52.810 57.120 ;
    END
  END N4BEG[2]
  PIN N4BEG[3]
    DIRECTION OUTPUT ;
    USE SIGNAL ;
    ANTENNADIFFAREA 0.702900 ;
    PORT
      LAYER met2 ;
        RECT 53.910 56.840 54.190 57.120 ;
    END
  END N4BEG[3]
  PIN N4BEG[4]
    DIRECTION OUTPUT ;
    USE SIGNAL ;
    ANTENNADIFFAREA 0.702900 ;
    PORT
      LAYER met2 ;
        RECT 55.290 56.840 55.570 57.120 ;
    END
  END N4BEG[4]
  PIN N4BEG[5]
    DIRECTION OUTPUT ;
    USE SIGNAL ;
    ANTENNADIFFAREA 0.702900 ;
    PORT
      LAYER met2 ;
        RECT 56.670 56.840 56.950 57.120 ;
    END
  END N4BEG[5]
  PIN N4BEG[6]
    DIRECTION OUTPUT ;
    USE SIGNAL ;
    ANTENNADIFFAREA 0.702900 ;
    PORT
      LAYER met2 ;
        RECT 58.050 56.840 58.330 57.120 ;
    END
  END N4BEG[6]
  PIN N4BEG[7]
    DIRECTION OUTPUT ;
    USE SIGNAL ;
    ANTENNADIFFAREA 0.702900 ;
    PORT
      LAYER met2 ;
        RECT 59.430 56.840 59.710 57.120 ;
    END
  END N4BEG[7]
  PIN N4BEG[8]
    DIRECTION OUTPUT ;
    USE SIGNAL ;
    ANTENNADIFFAREA 0.702900 ;
    PORT
      LAYER met2 ;
        RECT 60.810 56.840 61.090 57.120 ;
    END
  END N4BEG[8]
  PIN N4BEG[9]
    DIRECTION OUTPUT ;
    USE SIGNAL ;
    ANTENNADIFFAREA 0.702900 ;
    PORT
      LAYER met2 ;
        RECT 62.190 56.840 62.470 57.120 ;
    END
  END N4BEG[9]
  PIN NN4BEG[0]
    DIRECTION OUTPUT ;
    USE SIGNAL ;
    ANTENNADIFFAREA 0.702900 ;
    PORT
      LAYER met2 ;
        RECT 71.850 56.840 72.130 57.120 ;
    END
  END NN4BEG[0]
  PIN NN4BEG[10]
    DIRECTION OUTPUT ;
    USE SIGNAL ;
    ANTENNADIFFAREA 0.702900 ;
    PORT
      LAYER met2 ;
        RECT 85.650 56.840 85.930 57.120 ;
    END
  END NN4BEG[10]
  PIN NN4BEG[11]
    DIRECTION OUTPUT ;
    USE SIGNAL ;
    ANTENNADIFFAREA 0.702900 ;
    PORT
      LAYER met2 ;
        RECT 87.030 56.840 87.310 57.120 ;
    END
  END NN4BEG[11]
  PIN NN4BEG[12]
    DIRECTION OUTPUT ;
    USE SIGNAL ;
    ANTENNADIFFAREA 0.702900 ;
    PORT
      LAYER met2 ;
        RECT 88.410 56.840 88.690 57.120 ;
    END
  END NN4BEG[12]
  PIN NN4BEG[13]
    DIRECTION OUTPUT ;
    USE SIGNAL ;
    ANTENNADIFFAREA 0.702900 ;
    PORT
      LAYER met2 ;
        RECT 89.790 56.840 90.070 57.120 ;
    END
  END NN4BEG[13]
  PIN NN4BEG[14]
    DIRECTION OUTPUT ;
    USE SIGNAL ;
    ANTENNADIFFAREA 0.702900 ;
    PORT
      LAYER met2 ;
        RECT 91.170 56.840 91.450 57.120 ;
    END
  END NN4BEG[14]
  PIN NN4BEG[15]
    DIRECTION OUTPUT ;
    USE SIGNAL ;
    ANTENNADIFFAREA 0.702900 ;
    PORT
      LAYER met2 ;
        RECT 92.550 56.840 92.830 57.120 ;
    END
  END NN4BEG[15]
  PIN NN4BEG[1]
    DIRECTION OUTPUT ;
    USE SIGNAL ;
    ANTENNADIFFAREA 0.702900 ;
    PORT
      LAYER met2 ;
        RECT 73.230 56.840 73.510 57.120 ;
    END
  END NN4BEG[1]
  PIN NN4BEG[2]
    DIRECTION OUTPUT ;
    USE SIGNAL ;
    ANTENNADIFFAREA 0.702900 ;
    PORT
      LAYER met2 ;
        RECT 74.610 56.840 74.890 57.120 ;
    END
  END NN4BEG[2]
  PIN NN4BEG[3]
    DIRECTION OUTPUT ;
    USE SIGNAL ;
    ANTENNADIFFAREA 0.702900 ;
    PORT
      LAYER met2 ;
        RECT 75.990 56.840 76.270 57.120 ;
    END
  END NN4BEG[3]
  PIN NN4BEG[4]
    DIRECTION OUTPUT ;
    USE SIGNAL ;
    ANTENNADIFFAREA 0.702900 ;
    PORT
      LAYER met2 ;
        RECT 77.370 56.840 77.650 57.120 ;
    END
  END NN4BEG[4]
  PIN NN4BEG[5]
    DIRECTION OUTPUT ;
    USE SIGNAL ;
    ANTENNADIFFAREA 0.702900 ;
    PORT
      LAYER met2 ;
        RECT 78.750 56.840 79.030 57.120 ;
    END
  END NN4BEG[5]
  PIN NN4BEG[6]
    DIRECTION OUTPUT ;
    USE SIGNAL ;
    ANTENNADIFFAREA 0.702900 ;
    PORT
      LAYER met2 ;
        RECT 80.130 56.840 80.410 57.120 ;
    END
  END NN4BEG[6]
  PIN NN4BEG[7]
    DIRECTION OUTPUT ;
    USE SIGNAL ;
    ANTENNADIFFAREA 0.702900 ;
    PORT
      LAYER met2 ;
        RECT 81.510 56.840 81.790 57.120 ;
    END
  END NN4BEG[7]
  PIN NN4BEG[8]
    DIRECTION OUTPUT ;
    USE SIGNAL ;
    ANTENNADIFFAREA 0.702900 ;
    PORT
      LAYER met2 ;
        RECT 82.890 56.840 83.170 57.120 ;
    END
  END NN4BEG[8]
  PIN NN4BEG[9]
    DIRECTION OUTPUT ;
    USE SIGNAL ;
    ANTENNADIFFAREA 0.702900 ;
    PORT
      LAYER met2 ;
        RECT 84.270 56.840 84.550 57.120 ;
    END
  END NN4BEG[9]
  PIN N_GBUF_BEG[0]
    DIRECTION OUTPUT ;
    USE SIGNAL ;
    ANTENNADIFFAREA 0.702900 ;
    PORT
      LAYER met2 ;
        RECT 16.650 56.840 16.930 57.120 ;
    END
  END N_GBUF_BEG[0]
  PIN N_GBUF_BEG[1]
    DIRECTION OUTPUT ;
    USE SIGNAL ;
    ANTENNADIFFAREA 0.702900 ;
    PORT
      LAYER met2 ;
        RECT 18.030 56.840 18.310 57.120 ;
    END
  END N_GBUF_BEG[1]
  PIN N_GBUF_BEG[2]
    DIRECTION OUTPUT ;
    USE SIGNAL ;
    ANTENNADIFFAREA 0.702900 ;
    PORT
      LAYER met2 ;
        RECT 19.410 56.840 19.690 57.120 ;
    END
  END N_GBUF_BEG[2]
  PIN N_GBUF_BEG[3]
    DIRECTION OUTPUT ;
    USE SIGNAL ;
    ANTENNADIFFAREA 0.702900 ;
    PORT
      LAYER met2 ;
        RECT 20.790 56.840 21.070 57.120 ;
    END
  END N_GBUF_BEG[3]
  PIN S1END[0]
    DIRECTION INPUT ;
    USE SIGNAL ;
    ANTENNAGATEAREA 0.756000 ;
    PORT
      LAYER met2 ;
        RECT 95.310 56.840 95.590 57.120 ;
    END
  END S1END[0]
  PIN S1END[1]
    DIRECTION INPUT ;
    USE SIGNAL ;
    ANTENNAGATEAREA 0.756000 ;
    PORT
      LAYER met2 ;
        RECT 96.690 56.840 96.970 57.120 ;
    END
  END S1END[1]
  PIN S1END[2]
    DIRECTION INPUT ;
    USE SIGNAL ;
    ANTENNAGATEAREA 0.756000 ;
    PORT
      LAYER met2 ;
        RECT 98.070 56.840 98.350 57.120 ;
    END
  END S1END[2]
  PIN S1END[3]
    DIRECTION INPUT ;
    USE SIGNAL ;
    ANTENNAGATEAREA 1.625400 ;
    ANTENNADIFFAREA 0.869400 ;
    PORT
      LAYER met2 ;
        RECT 99.450 56.840 99.730 57.120 ;
    END
  END S1END[3]
  PIN S2END[0]
    DIRECTION INPUT ;
    USE SIGNAL ;
    ANTENNAGATEAREA 0.813000 ;
    PORT
      LAYER met2 ;
        RECT 111.870 56.840 112.150 57.120 ;
    END
  END S2END[0]
  PIN S2END[1]
    DIRECTION INPUT ;
    USE SIGNAL ;
    ANTENNAGATEAREA 0.813000 ;
    PORT
      LAYER met2 ;
        RECT 113.250 56.840 113.530 57.120 ;
    END
  END S2END[1]
  PIN S2END[2]
    DIRECTION INPUT ;
    USE SIGNAL ;
    ANTENNAGATEAREA 0.813000 ;
    PORT
      LAYER met2 ;
        RECT 114.630 56.840 114.910 57.120 ;
    END
  END S2END[2]
  PIN S2END[3]
    DIRECTION INPUT ;
    USE SIGNAL ;
    ANTENNAGATEAREA 0.813000 ;
    PORT
      LAYER met2 ;
        RECT 116.010 56.840 116.290 57.120 ;
    END
  END S2END[3]
  PIN S2END[4]
    DIRECTION INPUT ;
    USE SIGNAL ;
    ANTENNAGATEAREA 0.729000 ;
    PORT
      LAYER met2 ;
        RECT 117.390 56.840 117.670 57.120 ;
    END
  END S2END[4]
  PIN S2END[5]
    DIRECTION INPUT ;
    USE SIGNAL ;
    ANTENNAGATEAREA 0.729000 ;
    PORT
      LAYER met2 ;
        RECT 118.770 56.840 119.050 57.120 ;
    END
  END S2END[5]
  PIN S2END[6]
    DIRECTION INPUT ;
    USE SIGNAL ;
    ANTENNAGATEAREA 0.729000 ;
    PORT
      LAYER met2 ;
        RECT 120.150 56.840 120.430 57.120 ;
    END
  END S2END[6]
  PIN S2END[7]
    DIRECTION INPUT ;
    USE SIGNAL ;
    ANTENNAGATEAREA 0.729000 ;
    PORT
      LAYER met2 ;
        RECT 121.530 56.840 121.810 57.120 ;
    END
  END S2END[7]
  PIN S2MID[0]
    DIRECTION INPUT ;
    USE SIGNAL ;
    ANTENNAGATEAREA 0.603000 ;
    PORT
      LAYER met2 ;
        RECT 100.830 56.840 101.110 57.120 ;
    END
  END S2MID[0]
  PIN S2MID[1]
    DIRECTION INPUT ;
    USE SIGNAL ;
    ANTENNAGATEAREA 0.603000 ;
    PORT
      LAYER met2 ;
        RECT 102.210 56.840 102.490 57.120 ;
    END
  END S2MID[1]
  PIN S2MID[2]
    DIRECTION INPUT ;
    USE SIGNAL ;
    ANTENNAGATEAREA 0.603000 ;
    PORT
      LAYER met2 ;
        RECT 103.590 56.840 103.870 57.120 ;
    END
  END S2MID[2]
  PIN S2MID[3]
    DIRECTION INPUT ;
    USE SIGNAL ;
    ANTENNAGATEAREA 0.603000 ;
    PORT
      LAYER met2 ;
        RECT 104.970 56.840 105.250 57.120 ;
    END
  END S2MID[3]
  PIN S2MID[4]
    DIRECTION INPUT ;
    USE SIGNAL ;
    ANTENNAGATEAREA 0.603000 ;
    PORT
      LAYER met2 ;
        RECT 106.350 56.840 106.630 57.120 ;
    END
  END S2MID[4]
  PIN S2MID[5]
    DIRECTION INPUT ;
    USE SIGNAL ;
    ANTENNAGATEAREA 0.603000 ;
    PORT
      LAYER met2 ;
        RECT 107.730 56.840 108.010 57.120 ;
    END
  END S2MID[5]
  PIN S2MID[6]
    DIRECTION INPUT ;
    USE SIGNAL ;
    ANTENNAGATEAREA 0.603000 ;
    PORT
      LAYER met2 ;
        RECT 109.110 56.840 109.390 57.120 ;
    END
  END S2MID[6]
  PIN S2MID[7]
    DIRECTION INPUT ;
    USE SIGNAL ;
    ANTENNAGATEAREA 0.603000 ;
    PORT
      LAYER met2 ;
        RECT 110.490 56.840 110.770 57.120 ;
    END
  END S2MID[7]
  PIN S4END[0]
    DIRECTION INPUT ;
    USE SIGNAL ;
    ANTENNAGATEAREA 1.131000 ;
    PORT
      LAYER met2 ;
        RECT 122.910 56.840 123.190 57.120 ;
    END
  END S4END[0]
  PIN S4END[10]
    DIRECTION INPUT ;
    USE SIGNAL ;
    ANTENNAGATEAREA 0.477000 ;
    PORT
      LAYER met2 ;
        RECT 136.710 56.840 136.990 57.120 ;
    END
  END S4END[10]
  PIN S4END[11]
    DIRECTION INPUT ;
    USE SIGNAL ;
    ANTENNAGATEAREA 0.318000 ;
    PORT
      LAYER met2 ;
        RECT 138.090 56.840 138.370 57.120 ;
    END
  END S4END[11]
  PIN S4END[12]
    DIRECTION INPUT ;
    USE SIGNAL ;
    PORT
      LAYER met2 ;
        RECT 139.470 56.840 139.750 57.120 ;
    END
  END S4END[12]
  PIN S4END[13]
    DIRECTION INPUT ;
    USE SIGNAL ;
    PORT
      LAYER met2 ;
        RECT 140.850 56.840 141.130 57.120 ;
    END
  END S4END[13]
  PIN S4END[14]
    DIRECTION INPUT ;
    USE SIGNAL ;
    PORT
      LAYER met2 ;
        RECT 142.230 56.840 142.510 57.120 ;
    END
  END S4END[14]
  PIN S4END[15]
    DIRECTION INPUT ;
    USE SIGNAL ;
    PORT
      LAYER met2 ;
        RECT 143.610 56.840 143.890 57.120 ;
    END
  END S4END[15]
  PIN S4END[1]
    DIRECTION INPUT ;
    USE SIGNAL ;
    ANTENNAGATEAREA 1.290000 ;
    PORT
      LAYER met2 ;
        RECT 124.290 56.840 124.570 57.120 ;
    END
  END S4END[1]
  PIN S4END[2]
    DIRECTION INPUT ;
    USE SIGNAL ;
    ANTENNAGATEAREA 1.131000 ;
    PORT
      LAYER met2 ;
        RECT 125.670 56.840 125.950 57.120 ;
    END
  END S4END[2]
  PIN S4END[3]
    DIRECTION INPUT ;
    USE SIGNAL ;
    ANTENNAGATEAREA 1.290000 ;
    PORT
      LAYER met2 ;
        RECT 127.050 56.840 127.330 57.120 ;
    END
  END S4END[3]
  PIN S4END[4]
    DIRECTION INPUT ;
    USE SIGNAL ;
    ANTENNAGATEAREA 1.290000 ;
    PORT
      LAYER met2 ;
        RECT 128.430 56.840 128.710 57.120 ;
    END
  END S4END[4]
  PIN S4END[5]
    DIRECTION INPUT ;
    USE SIGNAL ;
    ANTENNAGATEAREA 1.290000 ;
    PORT
      LAYER met2 ;
        RECT 129.810 56.840 130.090 57.120 ;
    END
  END S4END[5]
  PIN S4END[6]
    DIRECTION INPUT ;
    USE SIGNAL ;
    ANTENNAGATEAREA 1.290000 ;
    PORT
      LAYER met2 ;
        RECT 131.190 56.840 131.470 57.120 ;
    END
  END S4END[6]
  PIN S4END[7]
    DIRECTION INPUT ;
    USE SIGNAL ;
    ANTENNAGATEAREA 1.290000 ;
    PORT
      LAYER met2 ;
        RECT 132.570 56.840 132.850 57.120 ;
    END
  END S4END[7]
  PIN S4END[8]
    DIRECTION INPUT ;
    USE SIGNAL ;
    ANTENNAGATEAREA 0.477000 ;
    PORT
      LAYER met2 ;
        RECT 133.950 56.840 134.230 57.120 ;
    END
  END S4END[8]
  PIN S4END[9]
    DIRECTION INPUT ;
    USE SIGNAL ;
    ANTENNAGATEAREA 0.318000 ;
    PORT
      LAYER met2 ;
        RECT 135.330 56.840 135.610 57.120 ;
    END
  END S4END[9]
  PIN SS4END[0]
    DIRECTION INPUT ;
    USE SIGNAL ;
    ANTENNAGATEAREA 0.444000 ;
    PORT
      LAYER met2 ;
        RECT 144.990 56.840 145.270 57.120 ;
    END
  END SS4END[0]
  PIN SS4END[10]
    DIRECTION INPUT ;
    USE SIGNAL ;
    ANTENNAGATEAREA 0.318000 ;
    PORT
      LAYER met2 ;
        RECT 158.790 56.840 159.070 57.120 ;
    END
  END SS4END[10]
  PIN SS4END[11]
    DIRECTION INPUT ;
    USE SIGNAL ;
    ANTENNAGATEAREA 0.318000 ;
    PORT
      LAYER met2 ;
        RECT 160.170 56.840 160.450 57.120 ;
    END
  END SS4END[11]
  PIN SS4END[12]
    DIRECTION INPUT ;
    USE SIGNAL ;
    ANTENNAGATEAREA 0.570000 ;
    PORT
      LAYER met2 ;
        RECT 161.550 56.840 161.830 57.120 ;
    END
  END SS4END[12]
  PIN SS4END[13]
    DIRECTION INPUT ;
    USE SIGNAL ;
    ANTENNAGATEAREA 0.570000 ;
    PORT
      LAYER met2 ;
        RECT 162.930 56.840 163.210 57.120 ;
    END
  END SS4END[13]
  PIN SS4END[14]
    DIRECTION INPUT ;
    USE SIGNAL ;
    ANTENNAGATEAREA 0.570000 ;
    PORT
      LAYER met2 ;
        RECT 164.310 56.840 164.590 57.120 ;
    END
  END SS4END[14]
  PIN SS4END[15]
    DIRECTION INPUT ;
    USE SIGNAL ;
    ANTENNAGATEAREA 0.570000 ;
    PORT
      LAYER met2 ;
        RECT 165.690 56.840 165.970 57.120 ;
    END
  END SS4END[15]
  PIN SS4END[1]
    DIRECTION INPUT ;
    USE SIGNAL ;
    ANTENNAGATEAREA 0.444000 ;
    PORT
      LAYER met2 ;
        RECT 146.370 56.840 146.650 57.120 ;
    END
  END SS4END[1]
  PIN SS4END[2]
    DIRECTION INPUT ;
    USE SIGNAL ;
    ANTENNAGATEAREA 0.444000 ;
    PORT
      LAYER met2 ;
        RECT 147.750 56.840 148.030 57.120 ;
    END
  END SS4END[2]
  PIN SS4END[3]
    DIRECTION INPUT ;
    USE SIGNAL ;
    ANTENNAGATEAREA 0.444000 ;
    PORT
      LAYER met2 ;
        RECT 149.130 56.840 149.410 57.120 ;
    END
  END SS4END[3]
  PIN SS4END[4]
    DIRECTION INPUT ;
    USE SIGNAL ;
    ANTENNAGATEAREA 0.444000 ;
    PORT
      LAYER met2 ;
        RECT 150.510 56.840 150.790 57.120 ;
    END
  END SS4END[4]
  PIN SS4END[5]
    DIRECTION INPUT ;
    USE SIGNAL ;
    ANTENNAGATEAREA 0.444000 ;
    PORT
      LAYER met2 ;
        RECT 151.890 56.840 152.170 57.120 ;
    END
  END SS4END[5]
  PIN SS4END[6]
    DIRECTION INPUT ;
    USE SIGNAL ;
    ANTENNAGATEAREA 0.444000 ;
    PORT
      LAYER met2 ;
        RECT 153.270 56.840 153.550 57.120 ;
    END
  END SS4END[6]
  PIN SS4END[7]
    DIRECTION INPUT ;
    USE SIGNAL ;
    ANTENNAGATEAREA 0.444000 ;
    PORT
      LAYER met2 ;
        RECT 154.650 56.840 154.930 57.120 ;
    END
  END SS4END[7]
  PIN SS4END[8]
    DIRECTION INPUT ;
    USE SIGNAL ;
    ANTENNAGATEAREA 0.318000 ;
    PORT
      LAYER met2 ;
        RECT 156.030 56.840 156.310 57.120 ;
    END
  END SS4END[8]
  PIN SS4END[9]
    DIRECTION INPUT ;
    USE SIGNAL ;
    ANTENNAGATEAREA 0.318000 ;
    PORT
      LAYER met2 ;
        RECT 157.410 56.840 157.690 57.120 ;
    END
  END SS4END[9]
  PIN VGND
    DIRECTION INOUT ;
    USE GROUND ;
    PORT
      LAYER met4 ;
        RECT 12.260 0.000 13.860 57.120 ;
    END
    PORT
      LAYER met4 ;
        RECT 42.260 0.000 43.860 57.120 ;
    END
    PORT
      LAYER met4 ;
        RECT 72.260 0.000 73.860 57.120 ;
    END
    PORT
      LAYER met4 ;
        RECT 102.260 0.000 103.860 57.120 ;
    END
    PORT
      LAYER met4 ;
        RECT 132.260 0.000 133.860 57.120 ;
    END
    PORT
      LAYER met4 ;
        RECT 162.260 0.000 163.860 57.120 ;
    END
    PORT
      LAYER met4 ;
        RECT 192.260 0.000 193.860 57.120 ;
    END
  END VGND
  PIN VPWR
    DIRECTION INOUT ;
    USE POWER ;
    PORT
      LAYER met4 ;
        RECT 6.960 0.000 8.560 57.120 ;
    END
    PORT
      LAYER met4 ;
        RECT 36.960 0.000 38.560 57.120 ;
    END
    PORT
      LAYER met4 ;
        RECT 66.960 0.000 68.560 57.120 ;
    END
    PORT
      LAYER met4 ;
        RECT 96.960 0.000 98.560 57.120 ;
    END
    PORT
      LAYER met4 ;
        RECT 126.960 0.000 128.560 57.120 ;
    END
    PORT
      LAYER met4 ;
        RECT 156.960 0.000 158.560 57.120 ;
    END
    PORT
      LAYER met4 ;
        RECT 186.960 0.000 188.560 57.120 ;
    END
  END VPWR
  PIN W_GBUF_FEED_BEG[0]
    DIRECTION OUTPUT ;
    USE SIGNAL ;
    ANTENNADIFFAREA 0.702900 ;
    PORT
      LAYER met3 ;
        RECT 0.000 1.400 0.600 2.000 ;
    END
  END W_GBUF_FEED_BEG[0]
  PIN W_GBUF_FEED_BEG[1]
    DIRECTION OUTPUT ;
    USE SIGNAL ;
    ANTENNADIFFAREA 0.702900 ;
    PORT
      LAYER met3 ;
        RECT 0.000 2.760 0.600 3.360 ;
    END
  END W_GBUF_FEED_BEG[1]
  PIN W_GBUF_FEED_BEG[2]
    DIRECTION OUTPUT ;
    USE SIGNAL ;
    ANTENNADIFFAREA 0.702900 ;
    PORT
      LAYER met3 ;
        RECT 0.000 4.120 0.600 4.720 ;
    END
  END W_GBUF_FEED_BEG[2]
  PIN W_GBUF_FEED_BEG[3]
    DIRECTION OUTPUT ;
    USE SIGNAL ;
    ANTENNADIFFAREA 0.702900 ;
    PORT
      LAYER met3 ;
        RECT 0.000 5.480 0.600 6.080 ;
    END
  END W_GBUF_FEED_BEG[3]
  PIN W_GBUF_FEED_END[0]
    DIRECTION INPUT ;
    USE SIGNAL ;
    ANTENNAGATEAREA 0.593700 ;
    ANTENNADIFFAREA 0.434700 ;
    PORT
      LAYER met3 ;
        RECT 210.080 1.400 210.680 2.000 ;
    END
  END W_GBUF_FEED_END[0]
  PIN W_GBUF_FEED_END[1]
    DIRECTION INPUT ;
    USE SIGNAL ;
    ANTENNAGATEAREA 0.593700 ;
    ANTENNADIFFAREA 0.434700 ;
    PORT
      LAYER met3 ;
        RECT 210.080 2.760 210.680 3.360 ;
    END
  END W_GBUF_FEED_END[1]
  PIN W_GBUF_FEED_END[2]
    DIRECTION INPUT ;
    USE SIGNAL ;
    ANTENNAGATEAREA 0.593700 ;
    ANTENNADIFFAREA 0.434700 ;
    PORT
      LAYER met3 ;
        RECT 210.080 4.120 210.680 4.720 ;
    END
  END W_GBUF_FEED_END[2]
  PIN W_GBUF_FEED_END[3]
    DIRECTION INPUT ;
    USE SIGNAL ;
    ANTENNAGATEAREA 0.593700 ;
    ANTENNADIFFAREA 0.434700 ;
    PORT
      LAYER met3 ;
        RECT 210.080 5.480 210.680 6.080 ;
    END
  END W_GBUF_FEED_END[3]
  OBS
      LAYER nwell ;
        RECT 2.570 2.635 208.110 54.590 ;
      LAYER li1 ;
        RECT 2.760 2.635 207.920 54.485 ;
      LAYER met1 ;
        RECT 2.760 0.380 207.920 56.740 ;
      LAYER met2 ;
        RECT 3.310 56.560 16.370 56.850 ;
        RECT 17.210 56.560 17.750 56.850 ;
        RECT 18.590 56.560 19.130 56.850 ;
        RECT 19.970 56.560 20.510 56.850 ;
        RECT 21.350 56.560 21.890 56.850 ;
        RECT 22.730 56.560 23.270 56.850 ;
        RECT 24.110 56.560 24.650 56.850 ;
        RECT 25.490 56.560 26.030 56.850 ;
        RECT 26.870 56.560 27.410 56.850 ;
        RECT 28.250 56.560 28.790 56.850 ;
        RECT 29.630 56.560 30.170 56.850 ;
        RECT 31.010 56.560 31.550 56.850 ;
        RECT 32.390 56.560 32.930 56.850 ;
        RECT 33.770 56.560 34.310 56.850 ;
        RECT 35.150 56.560 35.690 56.850 ;
        RECT 36.530 56.560 37.070 56.850 ;
        RECT 37.910 56.560 38.450 56.850 ;
        RECT 39.290 56.560 39.830 56.850 ;
        RECT 40.670 56.560 41.210 56.850 ;
        RECT 42.050 56.560 42.590 56.850 ;
        RECT 43.430 56.560 43.970 56.850 ;
        RECT 44.810 56.560 45.350 56.850 ;
        RECT 46.190 56.560 46.730 56.850 ;
        RECT 47.570 56.560 48.110 56.850 ;
        RECT 48.950 56.560 49.490 56.850 ;
        RECT 50.330 56.560 50.870 56.850 ;
        RECT 51.710 56.560 52.250 56.850 ;
        RECT 53.090 56.560 53.630 56.850 ;
        RECT 54.470 56.560 55.010 56.850 ;
        RECT 55.850 56.560 56.390 56.850 ;
        RECT 57.230 56.560 57.770 56.850 ;
        RECT 58.610 56.560 59.150 56.850 ;
        RECT 59.990 56.560 60.530 56.850 ;
        RECT 61.370 56.560 61.910 56.850 ;
        RECT 62.750 56.560 63.290 56.850 ;
        RECT 64.130 56.560 64.670 56.850 ;
        RECT 65.510 56.560 66.050 56.850 ;
        RECT 66.890 56.560 67.430 56.850 ;
        RECT 68.270 56.560 68.810 56.850 ;
        RECT 69.650 56.560 70.190 56.850 ;
        RECT 71.030 56.560 71.570 56.850 ;
        RECT 72.410 56.560 72.950 56.850 ;
        RECT 73.790 56.560 74.330 56.850 ;
        RECT 75.170 56.560 75.710 56.850 ;
        RECT 76.550 56.560 77.090 56.850 ;
        RECT 77.930 56.560 78.470 56.850 ;
        RECT 79.310 56.560 79.850 56.850 ;
        RECT 80.690 56.560 81.230 56.850 ;
        RECT 82.070 56.560 82.610 56.850 ;
        RECT 83.450 56.560 83.990 56.850 ;
        RECT 84.830 56.560 85.370 56.850 ;
        RECT 86.210 56.560 86.750 56.850 ;
        RECT 87.590 56.560 88.130 56.850 ;
        RECT 88.970 56.560 89.510 56.850 ;
        RECT 90.350 56.560 90.890 56.850 ;
        RECT 91.730 56.560 92.270 56.850 ;
        RECT 93.110 56.560 93.650 56.850 ;
        RECT 94.490 56.560 95.030 56.850 ;
        RECT 95.870 56.560 96.410 56.850 ;
        RECT 97.250 56.560 97.790 56.850 ;
        RECT 98.630 56.560 99.170 56.850 ;
        RECT 100.010 56.560 100.550 56.850 ;
        RECT 101.390 56.560 101.930 56.850 ;
        RECT 102.770 56.560 103.310 56.850 ;
        RECT 104.150 56.560 104.690 56.850 ;
        RECT 105.530 56.560 106.070 56.850 ;
        RECT 106.910 56.560 107.450 56.850 ;
        RECT 108.290 56.560 108.830 56.850 ;
        RECT 109.670 56.560 110.210 56.850 ;
        RECT 111.050 56.560 111.590 56.850 ;
        RECT 112.430 56.560 112.970 56.850 ;
        RECT 113.810 56.560 114.350 56.850 ;
        RECT 115.190 56.560 115.730 56.850 ;
        RECT 116.570 56.560 117.110 56.850 ;
        RECT 117.950 56.560 118.490 56.850 ;
        RECT 119.330 56.560 119.870 56.850 ;
        RECT 120.710 56.560 121.250 56.850 ;
        RECT 122.090 56.560 122.630 56.850 ;
        RECT 123.470 56.560 124.010 56.850 ;
        RECT 124.850 56.560 125.390 56.850 ;
        RECT 126.230 56.560 126.770 56.850 ;
        RECT 127.610 56.560 128.150 56.850 ;
        RECT 128.990 56.560 129.530 56.850 ;
        RECT 130.370 56.560 130.910 56.850 ;
        RECT 131.750 56.560 132.290 56.850 ;
        RECT 133.130 56.560 133.670 56.850 ;
        RECT 134.510 56.560 135.050 56.850 ;
        RECT 135.890 56.560 136.430 56.850 ;
        RECT 137.270 56.560 137.810 56.850 ;
        RECT 138.650 56.560 139.190 56.850 ;
        RECT 140.030 56.560 140.570 56.850 ;
        RECT 141.410 56.560 141.950 56.850 ;
        RECT 142.790 56.560 143.330 56.850 ;
        RECT 144.170 56.560 144.710 56.850 ;
        RECT 145.550 56.560 146.090 56.850 ;
        RECT 146.930 56.560 147.470 56.850 ;
        RECT 148.310 56.560 148.850 56.850 ;
        RECT 149.690 56.560 150.230 56.850 ;
        RECT 151.070 56.560 151.610 56.850 ;
        RECT 152.450 56.560 152.990 56.850 ;
        RECT 153.830 56.560 154.370 56.850 ;
        RECT 155.210 56.560 155.750 56.850 ;
        RECT 156.590 56.560 157.130 56.850 ;
        RECT 157.970 56.560 158.510 56.850 ;
        RECT 159.350 56.560 159.890 56.850 ;
        RECT 160.730 56.560 161.270 56.850 ;
        RECT 162.110 56.560 162.650 56.850 ;
        RECT 163.490 56.560 164.030 56.850 ;
        RECT 164.870 56.560 165.410 56.850 ;
        RECT 166.250 56.560 166.790 56.850 ;
        RECT 167.630 56.560 168.170 56.850 ;
        RECT 169.010 56.560 169.550 56.850 ;
        RECT 170.390 56.560 170.930 56.850 ;
        RECT 171.770 56.560 172.310 56.850 ;
        RECT 173.150 56.560 173.690 56.850 ;
        RECT 174.530 56.560 175.070 56.850 ;
        RECT 175.910 56.560 176.450 56.850 ;
        RECT 177.290 56.560 177.830 56.850 ;
        RECT 178.670 56.560 179.210 56.850 ;
        RECT 180.050 56.560 180.590 56.850 ;
        RECT 181.430 56.560 181.970 56.850 ;
        RECT 182.810 56.560 183.350 56.850 ;
        RECT 184.190 56.560 184.730 56.850 ;
        RECT 185.570 56.560 186.110 56.850 ;
        RECT 186.950 56.560 187.490 56.850 ;
        RECT 188.330 56.560 188.870 56.850 ;
        RECT 189.710 56.560 190.250 56.850 ;
        RECT 191.090 56.560 191.630 56.850 ;
        RECT 192.470 56.560 193.010 56.850 ;
        RECT 193.850 56.560 207.830 56.850 ;
        RECT 3.310 0.560 207.830 56.560 ;
        RECT 3.310 0.270 4.870 0.560 ;
        RECT 5.710 0.270 11.310 0.560 ;
        RECT 12.150 0.270 17.750 0.560 ;
        RECT 18.590 0.270 24.190 0.560 ;
        RECT 25.030 0.270 30.630 0.560 ;
        RECT 31.470 0.270 37.070 0.560 ;
        RECT 37.910 0.270 43.510 0.560 ;
        RECT 44.350 0.270 49.950 0.560 ;
        RECT 50.790 0.270 56.390 0.560 ;
        RECT 57.230 0.270 62.830 0.560 ;
        RECT 63.670 0.270 69.270 0.560 ;
        RECT 70.110 0.270 75.710 0.560 ;
        RECT 76.550 0.270 82.150 0.560 ;
        RECT 82.990 0.270 88.590 0.560 ;
        RECT 89.430 0.270 95.030 0.560 ;
        RECT 95.870 0.270 101.470 0.560 ;
        RECT 102.310 0.270 107.910 0.560 ;
        RECT 108.750 0.270 114.350 0.560 ;
        RECT 115.190 0.270 120.790 0.560 ;
        RECT 121.630 0.270 127.230 0.560 ;
        RECT 128.070 0.270 133.670 0.560 ;
        RECT 134.510 0.270 140.110 0.560 ;
        RECT 140.950 0.270 146.550 0.560 ;
        RECT 147.390 0.270 152.990 0.560 ;
        RECT 153.830 0.270 159.430 0.560 ;
        RECT 160.270 0.270 165.870 0.560 ;
        RECT 166.710 0.270 172.310 0.560 ;
        RECT 173.150 0.270 178.750 0.560 ;
        RECT 179.590 0.270 185.190 0.560 ;
        RECT 186.030 0.270 191.630 0.560 ;
        RECT 192.470 0.270 198.070 0.560 ;
        RECT 198.910 0.270 204.510 0.560 ;
        RECT 205.350 0.270 207.830 0.560 ;
      LAYER met3 ;
        RECT 0.600 55.440 210.080 56.265 ;
        RECT 1.000 1.000 209.680 55.440 ;
        RECT 0.600 0.855 210.080 1.000 ;
      LAYER met4 ;
        RECT 11.335 3.575 11.860 50.825 ;
        RECT 14.260 3.575 36.560 50.825 ;
        RECT 38.960 3.575 41.860 50.825 ;
        RECT 44.260 3.575 66.560 50.825 ;
        RECT 68.960 3.575 71.860 50.825 ;
        RECT 74.260 3.575 96.560 50.825 ;
        RECT 98.960 3.575 101.860 50.825 ;
        RECT 104.260 3.575 126.560 50.825 ;
        RECT 128.960 3.575 131.860 50.825 ;
        RECT 134.260 3.575 156.560 50.825 ;
        RECT 158.960 3.575 161.860 50.825 ;
        RECT 164.260 3.575 185.545 50.825 ;
  END
END S_IO4
END LIBRARY

